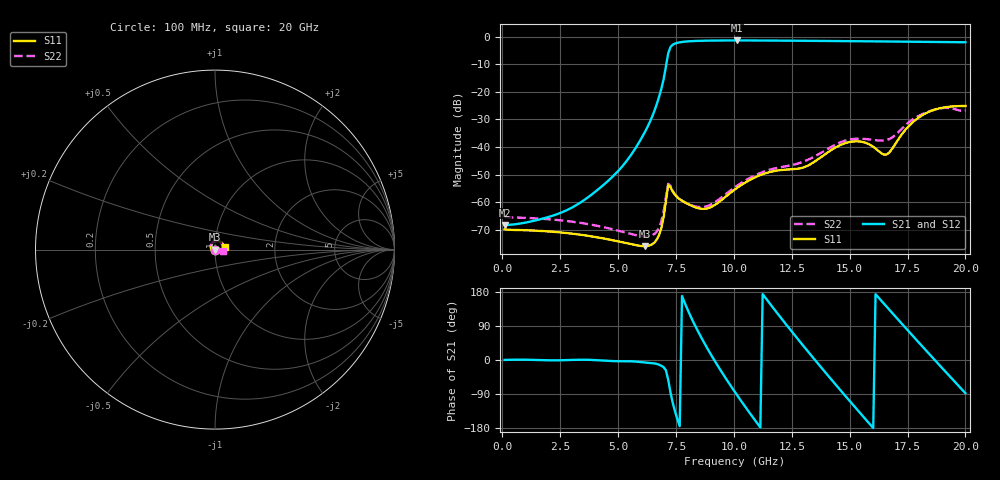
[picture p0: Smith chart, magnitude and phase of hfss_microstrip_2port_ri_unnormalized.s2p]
! Touchstone file exported from HFSS 2025.2.0
!  File:  C:/hfss/touchstone_fixtures.aedt
!  Generated:  12:36:34 AM Aug 26, 2026
!  Design:  microstrip
!  Project:  touchstone_fixtures
!  Setup:  Setup1
!  Solution:  Sweep
!Data is not renormalized
# GHz S RI
! Terminal data exported
! Port[1] = 1
! Port[2] = 2
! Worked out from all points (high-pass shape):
!   201 points, 100 MHz to 20 GHz, reference per port
!   highest |S21| = -1.38 dB at 10.15 GHz (marker M1); lowest = -68.3 dB at 100 MHz (marker M2)
!   |S21| within 3 dB of the highest: 7.237 GHz to end of sweep
!   lowest |S11| = -75.9 dB at 6.17 GHz (marker M3), VSWR 1.00
!   |S11| at or under -10 dB: start of sweep to end of sweep
!   |S22| runs from -72.4 to -25.8 dB; largest |S21 - S12| = 1.4e-14
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0.1  -0.000323 8.72e-06  0.000385 1.33e-06  0.000385 1.33e-06  -0.000542 1.13e-05
! Gamma 314.274619904661 -0.14406393139023 314.275157690951 -0.144553584415669
! Port Impedance 0.00118550628247278 0.621328204756136 0.00118477576393084 0.621308829002902
3.483  -0.000254 8.01e-07  0.00106 1.36e-05  0.00106 1.36e-05  -0.000415 6.47e-07
6.1695  -0.000159 1.31e-06  0.019 -0.00222  0.019 -0.00222  -0.000239 3.05e-07
6.7665  -0.000248 4.32e-05  0.0783 -0.0171  0.0783 -0.0171  -0.00034 5.06e-05
7.1645  0.000439 0.00198  0.3048 -0.3919  0.3048 -0.3919  0.00021 0.00214
7.3635  0.00147 -0.000504  -0.2866 -0.6561  -0.2866 -0.6561  0.00157 -0.000181
7.7615  -0.000288 -0.00102  -0.787 0.1555  -0.787 0.1555  3.49e-06 -0.00107
8.1595  -0.000841 -0.00021  -0.3075 0.7699  -0.3075 0.7699  -0.000736 -0.000493
8.458  -0.00069 0.000363  0.2179 0.8103  0.2179 0.8103  -0.000819 2.69e-06
9.1545  0.000537 0.000694  0.85 -0.00443  0.85 -0.00443  -0.000503 0.000842
10.05  0.000854 -0.00148  0.0775 -0.85  0.0775 -0.85  0.000873 0.00166
10.1495  0.000588 -0.00173  -0.0541 -0.8518  -0.0541 -0.8518  0.00112 0.00166
11.1445  -0.00309 -0.000168  -0.851 -0.0293  -0.851 -0.0293  0.00337 -0.000237
12.1395  0.000602 0.00381  -0.1891 0.8257  -0.1891 0.8257  0.00233 -0.00372
12.7365  0.00393 0.000856  0.4569 0.7094  0.4569 0.7094  0.000783 -0.00491
13.433  0.00124 -0.00509  0.8361 0.0762  0.8361 0.0762  -0.00144 -0.0064
14.826  -0.0095 0.00696  -0.0813 -0.8263  -0.0813 -0.8263  -0.0124 -0.00447
15.821  0.00656 0.00921  -0.7976 -0.2043  -0.7976 -0.2043  -0.013 0.0046
16.7165  0.000177 -0.00798  -0.5515 0.6027  -0.5515 0.6027  -0.0129 0.00541
17.5125  -0.0225 0.00449  0.166 0.7937  0.166 0.7937  -0.0232 0.0139
18.5075  -0.00325 0.0448  0.7875 0.1566  0.7875 0.1566  -0.00775 0.0446
20  0.0541 0.0123  0.0329 -0.7909  0.0329 -0.7909  0.0459 -0.00584
